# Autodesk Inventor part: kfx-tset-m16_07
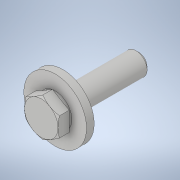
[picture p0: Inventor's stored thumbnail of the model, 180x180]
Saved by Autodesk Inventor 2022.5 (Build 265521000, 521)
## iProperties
Created: 2021-10
Part Number: kfx-tset-m16_07
Material: 一般
Document SubType Name: Modeling
Designer: ImaoCorp
Density: 1 g/cm^3
Appearance: 既定
Author: ImaoCorp
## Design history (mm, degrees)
feature "kfx-tset-m16_07"
node "ソリッド1"
